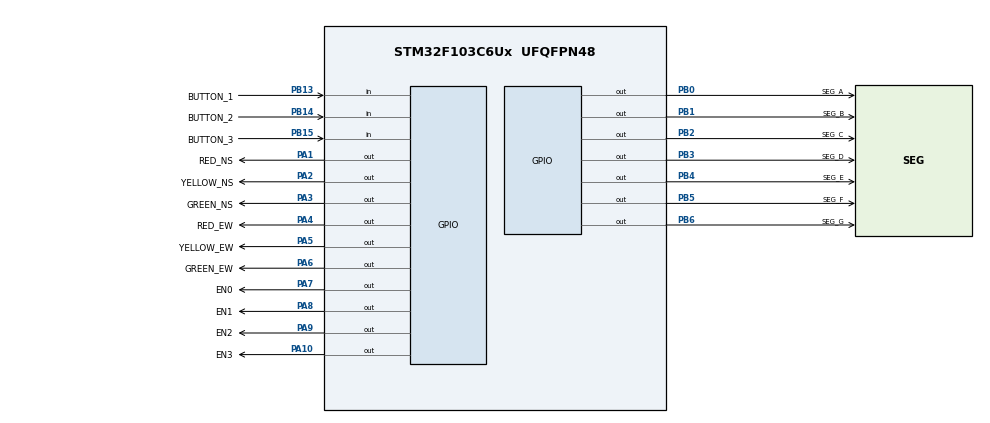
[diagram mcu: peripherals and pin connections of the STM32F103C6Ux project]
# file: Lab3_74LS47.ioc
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Mcu.Family=STM32F1
Mcu.Name=STM32F103C6Ux
Mcu.Package=UFQFPN48
NVIC.PriorityGroup=NVIC_PRIORITYGROUP_4
NVIC.TIM2_IRQn=true\:0\:0\:false\:false\:true\:true\:true
PA1.GPIO_Label=RED_NS
PA1.PinState=GPIO_PIN_SET
PA1.Signal=GPIO_Output
PA2.GPIO_Label=YELLOW_NS
PA2.PinState=GPIO_PIN_SET
PA2.Signal=GPIO_Output
PA3.GPIO_Label=GREEN_NS
PA3.PinState=GPIO_PIN_SET
PA3.Signal=GPIO_Output
PA4.GPIO_Label=RED_EW
PA4.PinState=GPIO_PIN_SET
PA4.Signal=GPIO_Output
PA5.GPIO_Label=YELLOW_EW
PA5.PinState=GPIO_PIN_SET
PA5.Signal=GPIO_Output
PA6.GPIO_Label=GREEN_EW
PA6.PinState=GPIO_PIN_SET
PA6.Signal=GPIO_Output
PA7.GPIO_Label=EN0
PA7.PinState=GPIO_PIN_SET
PA7.Signal=GPIO_Output
PA8.GPIO_Label=EN1
PA8.PinState=GPIO_PIN_SET
PA8.Signal=GPIO_Output
PA9.GPIO_Label=EN2
PA9.PinState=GPIO_PIN_SET
PA9.Signal=GPIO_Output
PA10.GPIO_Label=EN3
PA10.PinState=GPIO_PIN_SET
PA10.Signal=GPIO_Output
PB0.GPIO_Label=SEG_A
PB0.PinState=GPIO_PIN_SET
PB0.Signal=GPIO_Output
PB1.GPIO_Label=SEG_B
PB1.PinState=GPIO_PIN_SET
PB1.Signal=GPIO_Output
PB2.GPIO_Label=SEG_C
PB2.PinState=GPIO_PIN_SET
PB2.Signal=GPIO_Output
PB3.GPIO_Label=SEG_D
PB3.PinState=GPIO_PIN_SET
PB3.Signal=GPIO_Output
PB4.GPIO_Label=SEG_E
PB4.PinState=GPIO_PIN_SET
PB4.Signal=GPIO_Output
PB5.GPIO_Label=SEG_F
PB5.PinState=GPIO_PIN_SET
PB5.Signal=GPIO_Output
PB6.GPIO_Label=SEG_G
PB6.PinState=GPIO_PIN_SET
PB6.Signal=GPIO_Output
PB13.GPIO_Label=BUTTON_1
PB13.GPIO_PuPd=GPIO_PULLUP
PB13.Signal=GPIO_Input
PB14.GPIO_Label=BUTTON_2
PB14.GPIO_PuPd=GPIO_PULLUP
PB14.Signal=GPIO_Input
PB15.GPIO_Label=BUTTON_3
PB15.GPIO_PuPd=GPIO_PULLUP
PB15.Signal=GPIO_Input
ProjectManager.HeapSize=0x200
ProjectManager.StackSize=0x400
ProjectManager.TargetToolchain=STM32CubeIDE
RCC.APB1Freq_Value=8000000
RCC.APB2Freq_Value=8000000
TIM2.Period=9
TIM2.Prescaler=7999
VP_SYS_VS_ND.Mode=No_Debug
VP_TIM2_VS_ClockSourceINT.Mode=Internal
board=custom

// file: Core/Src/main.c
/* USER CODE BEGIN Header */
/**
  ******************************************************************************
  * @file           : main.c
  * @brief          : Main program body - Lab 3: Buttons/Switches & Traffic Light
  *                   MCU: STM32F103C6 (74LS47 Schematic Edition)
  ******************************************************************************
  */
/* USER CODE END Header */
#include "main.h"

/* USER CODE BEGIN Includes */
#include "timer.h"
#include "input_reading.h"
#include "led_display.h"
#include "input_processing.h"
/* USER CODE END Includes */

TIM_HandleTypeDef htim2;

void SystemClock_Config(void);
static void MX_GPIO_Init(void);
static void MX_TIM2_Init(void);

int main(void)
{
  HAL_Init();
  SystemClock_Config();

  MX_GPIO_Init();
  MX_TIM2_Init();
  /* USER CODE BEGIN 2 */
  HAL_TIM_Base_Start_IT(&htim2);
  fsm_init();
  /* USER CODE END 2 */

  while (1)
  {
    /* USER CODE BEGIN 3 */
    fsm_for_input_processing();
    /* Sleep CPU until next timer interrupt so Proteus VSM runs at 100% real-time speed */
    __WFI();
    /* USER CODE END 3 */
  }
}

void SystemClock_Config(void)
{
  RCC_OscInitTypeDef RCC_OscInitStruct = {0};
  RCC_ClkInitTypeDef RCC_ClkInitStruct = {0};

  RCC_OscInitStruct.OscillatorType = RCC_OSCILLATORTYPE_HSI;
  RCC_OscInitStruct.HSIState = RCC_HSI_ON;
  RCC_OscInitStruct.HSICalibrationValue = RCC_HSICALIBRATION_DEFAULT;
  RCC_OscInitStruct.PLL.PLLState = RCC_PLL_NONE;
  if (HAL_RCC_OscConfig(&RCC_OscInitStruct) != HAL_OK)
  {
    Error_Handler();
  }

  RCC_ClkInitStruct.ClockType = RCC_CLOCKTYPE_HCLK|RCC_CLOCKTYPE_SYSCLK
                              |RCC_CLOCKTYPE_PCLK1|RCC_CLOCKTYPE_PCLK2;
  RCC_ClkInitStruct.SYSCLKSource = RCC_SYSCLKSOURCE_HSI;
  RCC_ClkInitStruct.AHBCLKDivider = RCC_SYSCLK_DIV1;
  RCC_ClkInitStruct.APB1CLKDivider = RCC_HCLK_DIV1;
  RCC_ClkInitStruct.APB2CLKDivider = RCC_HCLK_DIV1;

  if (HAL_RCC_ClockConfig(&RCC_ClkInitStruct, FLASH_LATENCY_0) != HAL_OK)
  {
    Error_Handler();
  }
}

static void MX_TIM2_Init(void)
{
  TIM_ClockConfigTypeDef sClockSourceConfig = {0};
  TIM_MasterConfigTypeDef sMasterConfig = {0};

  htim2.Instance = TIM2;
  htim2.Init.Prescaler = 7999;
  htim2.Init.CounterMode = TIM_COUNTERMODE_UP;
  htim2.Init.Period = 9;
  htim2.Init.ClockDivision = TIM_CLOCKDIVISION_DIV1;
  htim2.Init.AutoReloadPreload = TIM_AUTORELOAD_PRELOAD_DISABLE;
  if (HAL_TIM_Base_Init(&htim2) != HAL_OK)
  {
    Error_Handler();
  }
  sClockSourceConfig.ClockSource = TIM_CLOCKSOURCE_INTERNAL;
  if (HAL_TIM_ConfigClockSource(&htim2, &sClockSourceConfig) != HAL_OK)
  {
    Error_Handler();
  }
  sMasterConfig.MasterOutputTrigger = TIM_TRGO_RESET;
  sMasterConfig.MasterSlaveMode = TIM_MASTERSLAVEMODE_DISABLE;
  if (HAL_TIMEx_MasterConfigSynchronization(&htim2, &sMasterConfig) != HAL_OK)
  {
    Error_Handler();
  }
  /* USER CODE BEGIN TIM2_Init 2 */
  /* Exercise 4: Automatically tie TIM2 hardware period to TIMER_CYCLE (ms) */
  if (htim2.Init.Period != (uint32_t)(TIMER_CYCLE - 1))
  {
    htim2.Init.Period = (uint32_t)(TIMER_CYCLE - 1);
    if (HAL_TIM_Base_Init(&htim2) != HAL_OK)
    {
      Error_Handler();
    }
  }
  /* USER CODE END TIM2_Init 2 */
}

static void MX_GPIO_Init(void)
{
  GPIO_InitTypeDef GPIO_InitStruct = {0};

  __HAL_RCC_GPIOA_CLK_ENABLE();
  __HAL_RCC_GPIOB_CLK_ENABLE();

  /* Initialize PA0..PA15 (BCD outputs to U3..U6) to 0 */
  HAL_GPIO_WritePin(GPIOA, GPIO_PIN_All, GPIO_PIN_RESET);

  /* Initialize GPIOB Traffic LEDs (PB8..PB13) & Set LED (PB0) OFF (SET), U2 BCD (PB4..PB7) to 0 */
  HAL_GPIO_WritePin(GPIOB, SET_LED_Pin|RED_NS_Pin|YELLOW_NS_Pin|GREEN_NS_Pin
                          |RED_EW_Pin|YELLOW_EW_Pin|GREEN_EW_Pin, GPIO_PIN_SET);
  HAL_GPIO_WritePin(GPIOB, U2_A_Pin|U2_B_Pin|U2_C_Pin|U2_D_Pin, GPIO_PIN_RESET);

  /* PA0..PA15: BCD Outputs */
  GPIO_InitStruct.Pin = GPIO_PIN_All;
  GPIO_InitStruct.Mode = GPIO_MODE_OUTPUT_PP;
  GPIO_InitStruct.Pull = GPIO_NOPULL;
  GPIO_InitStruct.Speed = GPIO_SPEED_FREQ_LOW;
  HAL_GPIO_Init(GPIOA, &GPIO_InitStruct);

  /* PB0, PB4..PB13: Traffic LEDs + U2 BCD + D13 Set LED Outputs */
  GPIO_InitStruct.Pin = SET_LED_Pin|U2_A_Pin|U2_B_Pin|U2_C_Pin|U2_D_Pin
                       |RED_NS_Pin|YELLOW_NS_Pin|GREEN_NS_Pin
                       |RED_EW_Pin|YELLOW_EW_Pin|GREEN_EW_Pin;
  GPIO_InitStruct.Mode = GPIO_MODE_OUTPUT_PP;
  GPIO_InitStruct.Pull = GPIO_NOPULL;
  GPIO_InitStruct.Speed = GPIO_SPEED_FREQ_LOW;
  HAL_GPIO_Init(GPIOB, &GPIO_InitStruct);

  /* PB1, PB2, PB3: 3 Button Inputs with Internal Pull-up */
  GPIO_InitStruct.Pin = BUTTON_1_Pin|BUTTON_2_Pin|BUTTON_3_Pin;
  GPIO_InitStruct.Mode = GPIO_MODE_INPUT;
  GPIO_InitStruct.Pull = GPIO_PULLUP;
  HAL_GPIO_Init(GPIOB, &GPIO_InitStruct);
}

void Error_Handler(void)
{
  __disable_irq();
  while (1)
  {
  }
}
